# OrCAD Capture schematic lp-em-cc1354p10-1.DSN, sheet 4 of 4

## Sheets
4 4_Mech: size A3

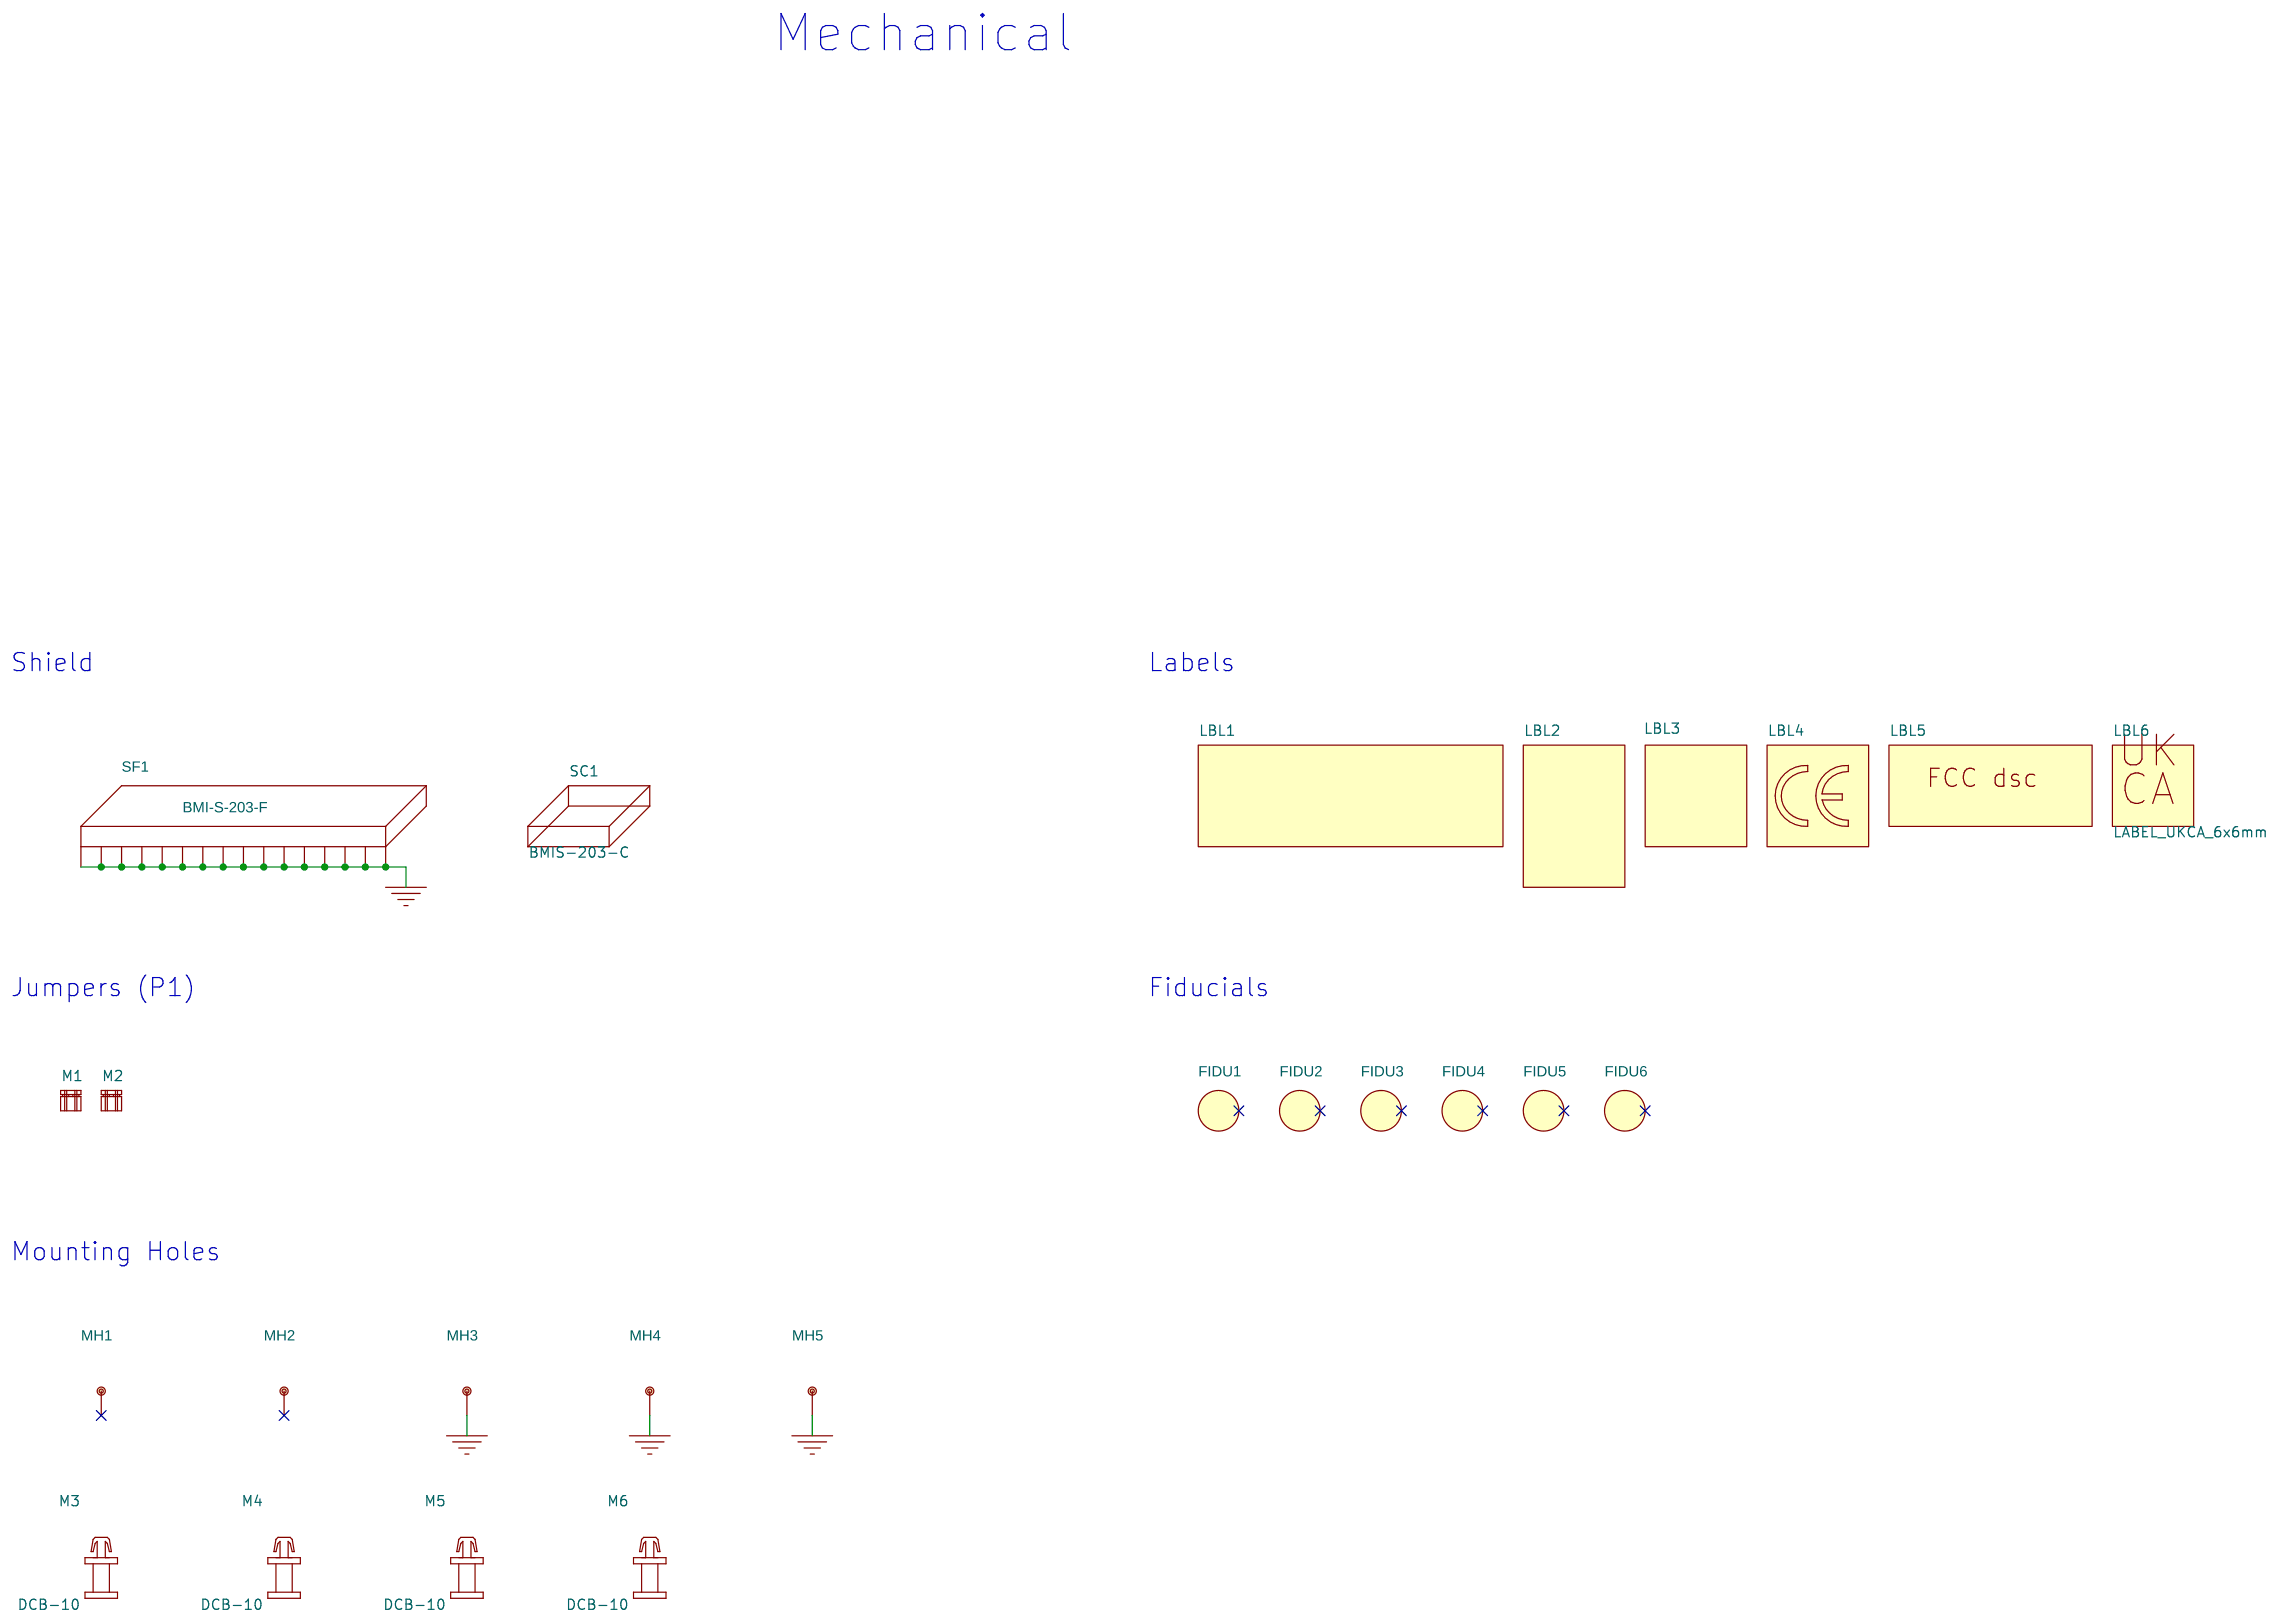
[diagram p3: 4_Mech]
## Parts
FIDU1  FIDU_1.27mm  [FID127X142]
FIDU2  FIDU_1.27mm  [FID127X142]
FIDU3  FIDU_1.27mm  [FID127X142]
FIDU4  FIDU_1.27mm  [FID127X142]
FIDU5  FIDU_1.27mm  [FID127X142]
FIDU6  FIDU_1.27mm  [FID127X142]
LBL1  TI_LOGO  [TI_LOGO_1]
LBL2  TRASH_7mm  [TRASH_7MM]
LBL3  ESD_LABEL_5x5mm  [ESD_LABEL_5X5]
LBL4  CE_label  [CE_MARKING]
LBL5  LABEL_FOR_EVALUATION_ONLY  [LABEL_FOR_EVALUATION_ONLY]
LBL6  LABEL_UKCA_6x6mm  [LABEL_UKCA_6MM]
M1  SNT-100-BK-G  [SAMTEC_SNT100BKG]
M2  SNT-100-BK-G  [SAMTEC_SNT100BKG]
M3  DCB-10  [MECH_DCB10_A2B]
M4  DCB-10  [MECH_DCB10_A2B]
M5  DCB-10  [MECH_DCB10_A2B]
M6  DCB-10  [MECH_DCB10_A2B]
MH1  HOLE_3.2mm_PAD_3.8mm_PTH  [MTG320_380]
MH2  HOLE_3.2mm_PAD_3.8mm_PTH  [MTG320_380]
MH3  HOLE_3.2mm_PAD_3.8mm_PTH  [MTG320_380]
MH4  HOLE_3.2mm_PAD_3.8mm_PTH  [MTG320_380]
MH5  HOLE_1.1mm_PTH  [MTG110_170]
SC1  BMIS-203-C  [MECH_BMIS203C]
SF1  BMI-S-203-F  [MECH_BMIS203_A2N]

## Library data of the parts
FIDU1-FIDU6 = FIDMARK: NON COMPONENT, FIDUCIAL MARK, ROUND 1.27MM, SMD; Additional Datasheet URL: N/A; CLASS: IO; Country of Origin: Missing Info; Datasheet URL: N/A; Mass: N/A; Mounting Type: SMD; NOTEfied URL: https://notefied-dynamic-precision.com/NOTEfiedWebInterface/part/show?partNumber=19-00300; Packing Size: N/A; Packing Type: Missing Info; Part Number: 19-00300; Part Type: Non Component|FIDUCIAL; ROHS: Missing Info; Revision: R018; Status: Released; Texas Part Status: Under Review; Type: Non Component; Vendor: NON_COMPONENT; Vendor Part Number: FIDUCIAL_1.27mm; Vendor Part Status: Active
LBL1 = TI_LOGO_V1: NON COMPONENT, LABEL, TEXAS INSTRUMENTS LOGO; Additional Datasheet URL: N/A; AutoDoc File: https://notefied-dynamic-precision.com/DB/Apps/Desktop/Item/Object.aspx?id=87770; BU Name: TEXAS INSTRUMENTS NORWAY; Country of Origin: Missing Info; Datasheet URL: N/A; Exclusive for Customers: TEXAS INSTRUMENTS NORWAY; Mass: N/A; Mounting Type: NOT APPLY; NOTEfied URL: https://notefied-dynamic-precision.com/NOTEfiedWebInterface/part/show?partNumber=19-00350; Notes: Custom Item; Packing Size: N/A; Packing Type: Missing Info; Part Number: 19-00350; Part Type: Non Component|LABEL; ROHS: Missing Info; Revision: R020; Status: Released; Texas Part Status: Under Review; Type: Non Component; Vendor: NON_COMPONENT; Vendor Part Status: Active
LBL2 = TRASH_V2: NON COMPONENT, LABEL, TRASH 7mm; Additional Datasheet URL: N/A; Country of Origin: Missing Info; Datasheet URL: N/A; Mass: N/A; Mounting Type: NOT APPLY; NOTEfied URL: https://notefied-dynamic-precision.com/NOTEfiedWebInterface/part/show?partNumber=19-01044; Packing Size: N/A; Packing Type: Missing Info; Part Number: 19-01044; Part Type: Non Component|LABEL; ROHS: Missing Info; Revision: R014; Status: Released; Texas Part Status: Under Review; Type: Non Component; Vendor: NON_COMPONENT; Vendor Part Status: Active
LBL3 = ESD_LABEL: NON COMPONENT, LABEL, ESD, 5 X 5 mm; Additional Datasheet URL: N/A; Country of Origin: Missing Info; Datasheet URL: N/A; Mass: N/A; Maximum Operating Temperature: N/A; Minimum Operating Temperature: N/A; Mounting Type: NOT APPLY; NOTEfied URL: https://notefied-dynamic-precision.com/NOTEfiedWebInterface/part/show?partNumber=19-00471; Packing Size: N/A; Packing Type: Missing Info; Part Number: 19-00471; Part Type: Non Component|LABEL; ROHS: Not Applicable; Revision: R009; Status: Released; Type: Non Component; Vendor: NON_COMPONENT; Vendor Part Status: Active
LBL4 = CE_LABEL_V1: NON COMPONENT, LABEL, CE; Additional Datasheet URL: N/A; Country of Origin: Missing Info; Datasheet URL: http://www.ce-marking.com/CE-marking-logo.html; Mass: N/A; Mounting Type: NOT APPLY; NOTEfied URL: https://notefied-dynamic-precision.com/NOTEfiedWebInterface/part/show?partNumber=19-00351; Packing Size: N/A; Packing Type: Missing Info; Part Number: 19-00351; Part Type: Non Component|LABEL; ROHS: Missing Info; Revision: R021; Status: Released; Texas Part Status: Under Review; Type: Non Component; Vendor: NON_COMPONENT; Vendor Part Number: CE_LABEL; Vendor Part Status: Active
LBL5 = LABEL_FOR_EVALUATOIN_ONLY: NON COMPONENT, LABEL, FOR EVALUATION ONLY, NOT FCC APPROVED FOR RESALE; Additional Datasheet URL: N/A; AutoDoc File: https://notefied-dynamic-precision.com/DB/Apps/Desktop/Item/Object.aspx?id=115268; BU Name: TEXAS INSTRUMENTS NORWAY; Datasheet URL: N/A; Exclusive for Customers: TEXAS INSTRUMENTS NORWAY; Mass: N/A; Maximum Operating Temperature: N/A; Minimum Operating Temperature: N/A; Mounting Type: NOT APPLY; NOTEfied URL: https://notefied-dynamic-precision.com/NOTEfiedWebInterface/part/show?partNumber=19-00830; Notes: Custom Item; Packing Size: N/A; Packing Type: Missing Info; Part Number: 19-00830; Part Type: Non Component|LABEL; REACH/SVHC Compliance: Missing Info; REACH/SVHC Details: N/A; REACH/SVHC Source: N/A; REACH/SVHC Status: Missing Info; ROHS: Missing Info; Revision: R020; Status: Released; Texas Part Status: Under Review; Type: Non Component; Vendor: NON_COMPONENT; Vendor Part Status: Active
LBL6 = LABEL_UKCA: NON COMPONENT, LABEL, UKCA, 6 X 6mm; Additional Datasheet URL: N/A; Datasheet URL: N/A; Maximum Operating Temperature: N/A; Minimum Operating Temperature: N/A; Mounting Type: NOT APPLY; NOTEfied URL: https://notefied-dynamic-precision.com/NOTEfiedWebInterface/part/show?partNumber=19-01541; Part Number: 19-01541; Part Type: Non Component|LABEL; REACH/SVHC Details: SVHC List Version; ROHS: Not Applicable; Revision: R001; Status: Released; Texas Part Status: Under Review; Type: Non Component; Vendor: NON_COMPONENT; Vendor Part Status: Active
M1 M2 = MECH_SHUNT_JUMPER_V1: MECHANIC, SHUNT, CURRENT RATING 4.3A PER PIN, 2.54 X 5.08 X 6.1mm, BLACK; Additional Datasheet URL: https://suddendocs.samtec.com/prints/snt-100-xx-x-x-mkt.pdf; AutoDoc File: https://notefied-dynamic-precision.com/DB/Apps/Desktop/Item/Object.aspx?id=104092; BU Name: DYNAMIC PRECISION GDANSK; Budget Currency: USD; Budget Price: 0.146; Budgetary Price: 0.14525 USD; Client Status: UNDER_REVIEW; Country of Origin: China,Costa Rica,Malaysia,Singapore,Taiwan,United States,Vietnam; Datasheet URL: https://suddendocs.samtec.com/catalog_english/snt.pdf; Datasheet URL 1: http://suddendocs.samtec.com/catalog_english/snt.pdf; Datasheet URL 2: http://suddendocs.samtec.com/prints/snt-100-xx-x-x-mkt.pdf; Mass: 0.11724g; Max Oper Temp: +125DEGC; Maximum Operating Temperature: +125DEGC; Min Oper Temp: -55DEGC; Minimum Operating Temperature: -55DEGC; Mounting Type: NOT APPLY; NOTEfied URL: https://notefied-dynamic-precision.com/NOTEfiedWebInterface/part/show?partNumber=19-00498; Packing Size: 1; Packing Type: Bulk; Part Number: 19-00498; Part Type: Mechanic|SHUNT; REACH/SVHC Compliance: Compliant; REACH/SVHC Details: SVHC List Version Dec 17, 2015; REACH/SVHC Source: Material Declaration; REACH/SVHC Status: Unaffected; REACH/SVHC_COMPLIANCE: COMPLIANT; REACH/SVHC_DETAILS: SVHC LIST VERSION Dec 17, 2015; REACH/SVHC_SOURCE: MATERIAL DECLARATION; REACH/SVHC_STATUS: UNAFFECTED; ROHS: Compliant; Rated Current: 4.3A; Revision: R024; RoHS Status: ROHS_COMPLIANT; Rtd Current: 4.3A; Status: Released; Texas Part Status: Under Review; Type: Mechanic; Vendor: SAMTEC; Vendor Part Status: Active; Weight: 0.11724g
M3-M6 = MECH_SPACERS_SUPPORT_V1: MECHANIC, ACCESSORY, SPACER SUPPORT, PCB DIA. 3mm, NYLON 66, NPTH; Additional Datasheet URL: https://www.kangyang-europe.com/wp-content/uploads/2020/02/DCB-H.pdf; Datasheet URL: https://www.kangyang-europe.com/product/pc-board-hardware/dcb-10/; Exclusive for Customers: TEXAS INSTRUMENTS NORWAY; Mass: N/A; Maximum Operating Temperature: N/A; Minimum Operating Temperature: N/A; Mounting Type: NPTH; NOTEfied URL: https://notefied-dynamic-precision.com/NOTEfiedWebInterface/part/show?partNumber=13-04664; Notes: Custom libraries; Packing Size: N/A; Packing Type: Missing Info; Part Number: 13-04664; Part Type: Mechanic|ACCESSORY; REACH/SVHC Compliance: Compliant; REACH/SVHC Details: SVHC List Version Jul 7, 2017; REACH/SVHC Source: REACH Declaration; REACH/SVHC Status: Unaffected; ROHS: Compliant; Revision: R015; Status: Released; Texas Part Status: Under Review; Type: Mechanic; Vendor: SUZHOU SOLY ELECTRICIAN; Vendor Part Status: Active
MH1-MH4 = HOLE_PTH: NON COMPONENT, HOLE 3.2mm, PLATED, PAD SIZE 3.8mm; Additional Datasheet URL: N/A; Country of Origin: Missing Info; Datasheet URL: N/A; Mass: N/A; Mounting Type: NOT APPLY; NOTEfied URL: https://notefied-dynamic-precision.com/NOTEfiedWebInterface/part/show?partNumber=19-00083; Packing Size: N/A; Packing Type: Missing Info; Part Number: 19-00083; Part Type: Non Component|HOLE|PLATED; ROHS: Missing Info; Revision: R020; Status: Released; Type: Non Component; Vendor: NON_COMPONENT; Vendor Part Status: Active
MH5 = HOLE_PTH: NON COMPONENT, HOLE 1.1mm, PLATED, PAD SIZE 1.7mm; Additional Datasheet URL: N/A; Country of Origin: Missing Info; Datasheet URL: N/A; Mass: N/A; Mounting Type: NOT APPLY; NOTEfied URL: https://notefied-dynamic-precision.com/NOTEfiedWebInterface/part/show?partNumber=19-00062; Packing Size: N/A; Packing Type: Missing Info; Part Number: 19-00062; Part Type: Non Component|HOLE|PLATED; ROHS: Missing Info; Revision: R007; Status: Released; Type: Non Component; Vendor: NON_COMPONENT; Vendor Part Number: HOLE_1.1mm_PLATED; Vendor Part Status: Active
SC1 = SHIELD_COVER: MECHANIC, COVER FOR SHIELD BMI-S-203; Additional Datasheet URL: https://www.laird.com/sites/default/files/2018-11/EMI-CAT-Essentials%201213.pdf; Budgetary Price: 0.85209 USD; Country of Origin: Czech Republic; Datasheet URL: https://www.laird.com/sites/default/files/2018-11/Board%20Level%20Shields%20Catalog%20Download.pdf; Lead Time: 4; Mass: 1g; Maximum Operating Temperature: +85DEGC; Minimum Operating Temperature: -40DEGC; Mounting Type: NOT APPLY; NOTEfied URL: https://notefied-dynamic-precision.com/NOTEfiedWebInterface/part/show?partNumber=13-00422; Packing Size: 300; Packing Type: Tape & Reel; Part Number: 13-00422; Part Type: Mechanic|SHIELD; REACH/SVHC Compliance: Compliant; REACH/SVHC Details: SVHC List Version Jan 12, 2017; REACH/SVHC Source: REACH Declaration; REACH/SVHC Status: Unaffected; ROHS: Compliant; Revision: R022; Status: Released; Texas Part Status: Under Review; Type: Mechanic; Vendor: LAIRD; Vendor Part Number: BMI-S-203-C; Vendor Part Status: Active
SF1 = SHIELD_COVER_BMIS-203: MECHANIC, FRAME FOR SHIELD BMI-S-203, SMD; Additional Datasheet URL: https://www.laird.com/sites/default/files/2018-11/EMI-CAT-Essentials%201213.pdf; Budgetary Price: 1.37655 USD; CLASS: IC; Country of Origin: Czech Republic; Datasheet URL: https://www.laird.com/sites/default/files/2018-11/Board%20Level%20Shields%20Catalog%20Download.pdf; Lead Time: 4; Mass: 1g; Maximum Operating Temperature: +85DEGC; Minimum Operating Temperature: -40DEGC; Mounting Type: SMD; NOTEfied URL: https://notefied-dynamic-precision.com/NOTEfiedWebInterface/part/show?partNumber=13-00133; Packing Size: 300; Packing Type: Tape & Reel; Part Number: 13-00133; Part Type: Mechanic|SHIELD; REACH/SVHC Compliance: Compliant; REACH/SVHC Details: SVHC List Version Jan 15, 2018; REACH/SVHC Source: REACH Declaration; REACH/SVHC Status: Unaffected; ROHS: Compliant; Revision: R025; Status: Released; Texas Part Status: Under Review; Type: Mechanic; Vendor: LAIRD; Vendor Part Status: Active

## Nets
GND: MH3.1 MH4.1 MH5.1 SF1.1(GND) SF1.2(GND) SF1.3(GND) SF1.4(GND) SF1.5(GND) SF1.6(GND) SF1.7(GND) SF1.8(GND) SF1.9(GND) SF1.10(GND) SF1.11(GND) SF1.12(GND) SF1.13(GND) SF1.14(GND) SF1.15(GND) SF1.16(GND) ; also on sheet 1 2 3

Not connected (* = marked no-connect by the designer): FIDU1 1*; FIDU2 1*; FIDU3 1*; FIDU4 1*; FIDU5 1*; FIDU6 1*; MH1 1*; MH2 1*

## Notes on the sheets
sheet 4
- Mechanical
- Shield
- Labels
- Jumpers (P1)
- Fiducials
- Mounting Holes
